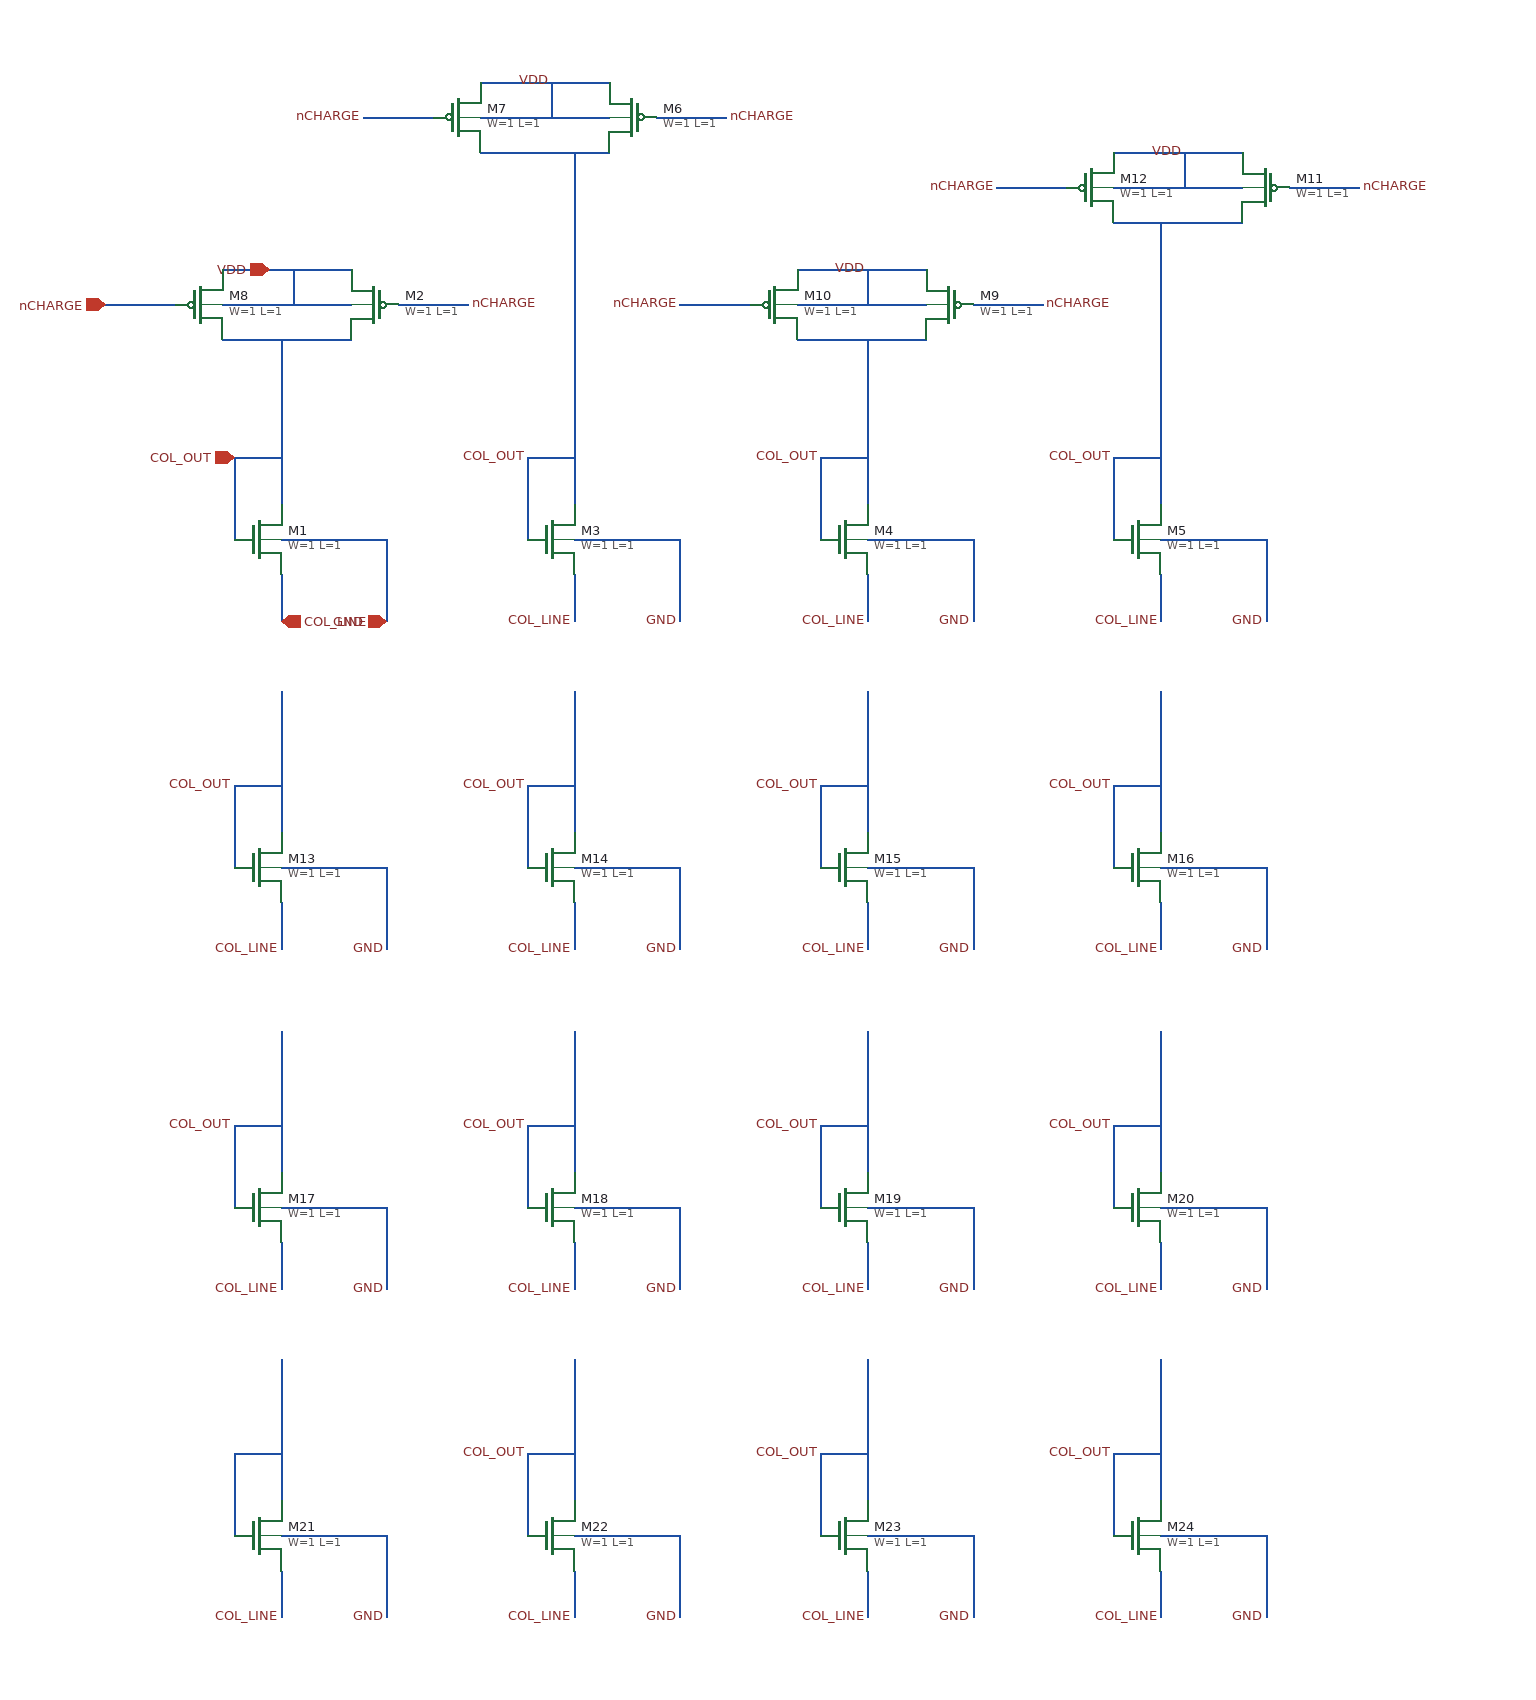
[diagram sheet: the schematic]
v {xschem version=3.4.8RC file_version=1.3}
G {}
K {}
V {}
S {}
F {}
E {}
P 4 1 -120 -60 {}
N 0 -80 0 40 {lab=COL_OUT}
N -40 0 -40 70 {lab=COL_OUT}
N -40 0 0 0 {lab=COL_OUT}
N 0 100 0 140 {lab=COL_LINE}
N 0 70 90 70 {lab=GND}
N 90 70 90 140 {lab=GND}
N 250 -80 250 40 {lab=COL_OUT}
N 210 0 210 70 {lab=COL_OUT}
N 210 0 250 0 {lab=COL_OUT}
N 250 100 250 140 {lab=COL_LINE}
N 250 70 340 70 {lab=GND}
N 340 70 340 140 {lab=GND}
N 500 -80 500 40 {lab=COL_OUT}
N 460 0 460 70 {lab=COL_OUT}
N 460 0 500 0 {lab=COL_OUT}
N 500 100 500 140 {lab=COL_LINE}
N 500 70 590 70 {lab=GND}
N 590 70 590 140 {lab=GND}
N 750 -80 750 40 {lab=COL_OUT}
N 710 0 710 70 {lab=COL_OUT}
N 710 0 750 0 {lab=COL_OUT}
N 750 100 750 140 {lab=COL_LINE}
N 750 70 840 70 {lab=GND}
N 840 70 840 140 {lab=GND}
N 320 -290 380 -290 {lab=nCHARGE}
N 70 -290 130 -290 {lab=nCHARGE}
N 170 -260 280 -260 {lab=COL_OUT}
N 250 -260 250 -80 {lab=COL_OUT}
N 170 -290 280 -290 {lab=VDD}
N 170 -320 280 -320 {lab=VDD}
N 230 -320 230 -290 {lab=VDD}
N 100 -130 160 -130 {lab=nCHARGE}
N -150 -130 -90 -130 {lab=nCHARGE}
N -50 -130 60 -130 {lab=VDD}
N -50 -160 60 -160 {lab=VDD}
N 10 -160 10 -130 {lab=VDD}
N -50 -100 60 -100 {lab=COL_OUT}
N 0 -100 0 -80 {lab=COL_OUT}
N 590 -130 650 -130 {lab=nCHARGE}
N 340 -130 400 -130 {lab=nCHARGE}
N 440 -130 550 -130 {lab=VDD}
N 440 -160 550 -160 {lab=VDD}
N 500 -160 500 -130 {lab=VDD}
N 440 -100 550 -100 {lab=COL_OUT}
N 500 -100 500 -80 {lab=COL_OUT}
N 860 -230 920 -230 {lab=nCHARGE}
N 610 -230 670 -230 {lab=nCHARGE}
N 710 -230 820 -230 {lab=VDD}
N 710 -260 820 -260 {lab=VDD}
N 770 -260 770 -230 {lab=VDD}
N 750 -200 750 -80 {lab=COL_OUT}
N 710 -200 820 -200 {lab=COL_OUT}
N 0 200 0 320 {lab=COL_OUT}
N -40 280 -40 350 {lab=COL_OUT}
N -40 280 0 280 {lab=COL_OUT}
N 0 380 0 420 {lab=#net1}
N 0 350 90 350 {lab=#net2}
N 90 350 90 420 {lab=#net2}
N 250 200 250 320 {lab=COL_OUT}
N 210 280 210 350 {lab=COL_OUT}
N 210 280 250 280 {lab=COL_OUT}
N 250 380 250 420 {lab=COL_LINE}
N 250 350 340 350 {lab=GND}
N 340 350 340 420 {lab=GND}
N 500 200 500 320 {lab=COL_OUT}
N 460 280 460 350 {lab=COL_OUT}
N 460 280 500 280 {lab=COL_OUT}
N 500 380 500 420 {lab=COL_LINE}
N 500 350 590 350 {lab=GND}
N 590 350 590 420 {lab=GND}
N 750 200 750 320 {lab=COL_OUT}
N 710 280 710 350 {lab=COL_OUT}
N 710 280 750 280 {lab=COL_OUT}
N 750 380 750 420 {lab=COL_LINE}
N 750 350 840 350 {lab=GND}
N 840 350 840 420 {lab=GND}
N 0 490 0 610 {lab=COL_OUT}
N -40 570 -40 640 {lab=COL_OUT}
N -40 570 0 570 {lab=COL_OUT}
N 0 670 0 710 {lab=#net3}
N 0 640 90 640 {lab=#net4}
N 90 640 90 710 {lab=#net4}
N 250 490 250 610 {lab=COL_OUT}
N 210 570 210 640 {lab=COL_OUT}
N 210 570 250 570 {lab=COL_OUT}
N 250 670 250 710 {lab=COL_LINE}
N 250 640 340 640 {lab=GND}
N 340 640 340 710 {lab=GND}
N 500 490 500 610 {lab=COL_OUT}
N 460 570 460 640 {lab=COL_OUT}
N 460 570 500 570 {lab=COL_OUT}
N 500 670 500 710 {lab=COL_LINE}
N 500 640 590 640 {lab=GND}
N 590 640 590 710 {lab=GND}
N 750 490 750 610 {lab=COL_OUT}
N 710 570 710 640 {lab=COL_OUT}
N 710 570 750 570 {lab=COL_OUT}
N 750 670 750 710 {lab=COL_LINE}
N 750 640 840 640 {lab=GND}
N 840 640 840 710 {lab=GND}
N 0 770 0 890 {lab=#net5}
N -40 850 -40 920 {lab=#net5}
N -40 850 0 850 {lab=#net5}
N 0 950 0 990 {lab=#net6}
N 0 920 90 920 {lab=#net7}
N 90 920 90 990 {lab=#net7}
N 250 770 250 890 {lab=COL_OUT}
N 210 850 210 920 {lab=COL_OUT}
N 210 850 250 850 {lab=COL_OUT}
N 250 950 250 990 {lab=COL_LINE}
N 250 920 340 920 {lab=GND}
N 340 920 340 990 {lab=GND}
N 500 770 500 890 {lab=COL_OUT}
N 460 850 460 920 {lab=COL_OUT}
N 460 850 500 850 {lab=COL_OUT}
N 500 950 500 990 {lab=COL_LINE}
N 500 920 590 920 {lab=GND}
N 590 920 590 990 {lab=GND}
N 750 770 750 890 {lab=COL_OUT}
N 710 850 710 920 {lab=COL_OUT}
N 710 850 750 850 {lab=COL_OUT}
N 750 950 750 990 {lab=COL_LINE}
N 750 920 840 920 {lab=GND}
N 840 920 840 990 {lab=GND}
C {sky130_fd_pr/nfet_01v8.sym} -20 70 0 0 {name=M1
W=1
L=1
nf=1 
mult=1
ad="expr('int((@nf + 1)/2) * @W / @nf * 0.29')"
pd="expr('2*int((@nf + 1)/2) * (@W / @nf + 0.29)')"
as="expr('int((@nf + 2)/2) * @W / @nf * 0.29')"
ps="expr('2*int((@nf + 2)/2) * (@W / @nf + 0.29)')"
nrd="expr('0.29 / @W ')" nrs="expr('0.29 / @W ')"
sa=0 sb=0 sd=0
model=nfet_01v8
spiceprefix=X
}
C {ipin.sym} -150 -130 0 0 {name=p1 lab=nCHARGE}
C {opin.sym} -40 0 0 1 {name=p2 lab=COL_OUT}
C {iopin.sym} -10 -160 3 0 {name=p3 lab=VDD}
C {iopin.sym} 90 140 0 0 {name=p5 lab=GND}
C {iopin.sym} 0 140 0 1 {name=p6 lab=COL_LINE}
C {sky130_fd_pr/nfet_01v8.sym} 230 70 0 0 {name=M3
W=1
L=1
nf=1 
mult=1
ad="expr('int((@nf + 1)/2) * @W / @nf * 0.29')"
pd="expr('2*int((@nf + 1)/2) * (@W / @nf + 0.29)')"
as="expr('int((@nf + 2)/2) * @W / @nf * 0.29')"
ps="expr('2*int((@nf + 2)/2) * (@W / @nf + 0.29)')"
nrd="expr('0.29 / @W ')" nrs="expr('0.29 / @W ')"
sa=0 sb=0 sd=0
model=nfet_01v8
spiceprefix=X
}
C {sky130_fd_pr/nfet_01v8.sym} 480 70 0 0 {name=M4
W=1
L=1
nf=1 
mult=1
ad="expr('int((@nf + 1)/2) * @W / @nf * 0.29')"
pd="expr('2*int((@nf + 1)/2) * (@W / @nf + 0.29)')"
as="expr('int((@nf + 2)/2) * @W / @nf * 0.29')"
ps="expr('2*int((@nf + 2)/2) * (@W / @nf + 0.29)')"
nrd="expr('0.29 / @W ')" nrs="expr('0.29 / @W ')"
sa=0 sb=0 sd=0
model=nfet_01v8
spiceprefix=X
}
C {sky130_fd_pr/nfet_01v8.sym} 730 70 0 0 {name=M5
W=1
L=1
nf=1 
mult=1
ad="expr('int((@nf + 1)/2) * @W / @nf * 0.29')"
pd="expr('2*int((@nf + 1)/2) * (@W / @nf + 0.29)')"
as="expr('int((@nf + 2)/2) * @W / @nf * 0.29')"
ps="expr('2*int((@nf + 2)/2) * (@W / @nf + 0.29)')"
nrd="expr('0.29 / @W ')" nrs="expr('0.29 / @W ')"
sa=0 sb=0 sd=0
model=nfet_01v8
spiceprefix=X
}
C {lab_wire.sym} 210 0 0 0 {name=p7 sig_type=std_logic lab=COL_OUT}
C {lab_wire.sym} 250 140 0 0 {name=p10 sig_type=std_logic lab=COL_LINE
}
C {lab_wire.sym} 340 140 0 0 {name=p8 sig_type=std_logic lab=GND
}
C {lab_wire.sym} 460 0 0 0 {name=p9 sig_type=std_logic lab=COL_OUT}
C {lab_wire.sym} 500 140 0 0 {name=p11 sig_type=std_logic lab=COL_LINE
}
C {lab_wire.sym} 590 140 0 0 {name=p12 sig_type=std_logic lab=GND
}
C {lab_wire.sym} 710 0 0 0 {name=p13 sig_type=std_logic lab=COL_OUT}
C {lab_wire.sym} 750 140 0 0 {name=p14 sig_type=std_logic lab=COL_LINE
}
C {lab_wire.sym} 840 140 0 0 {name=p15 sig_type=std_logic lab=GND
}
C {sky130_fd_pr/pfet_01v8.sym} 300 -290 0 1 {name=M6
W=1
L=1
nf=1
mult=1
ad="expr('int((@nf + 1)/2) * @W / @nf * 0.29')"
pd="expr('2*int((@nf + 1)/2) * (@W / @nf + 0.29)')"
as="expr('int((@nf + 2)/2) * @W / @nf * 0.29')"
ps="expr('2*int((@nf + 2)/2) * (@W / @nf + 0.29)')"
nrd="expr('0.29 / @W ')" nrs="expr('0.29 / @W ')"
sa=0 sb=0 sd=0
model=pfet_01v8
spiceprefix=X
}
C {sky130_fd_pr/pfet_01v8.sym} 150 -290 0 0 {name=M7
W=1
L=1
nf=1
mult=1
ad="expr('int((@nf + 1)/2) * @W / @nf * 0.29')"
pd="expr('2*int((@nf + 1)/2) * (@W / @nf + 0.29)')"
as="expr('int((@nf + 2)/2) * @W / @nf * 0.29')"
ps="expr('2*int((@nf + 2)/2) * (@W / @nf + 0.29)')"
nrd="expr('0.29 / @W ')" nrs="expr('0.29 / @W ')"
sa=0 sb=0 sd=0
model=pfet_01v8
spiceprefix=X
}
C {lab_wire.sym} 200 -320 0 1 {name=p16 sig_type=std_logic lab=VDD}
C {lab_wire.sym} 70 -290 0 0 {name=p18 sig_type=std_logic lab=nCHARGE}
C {lab_wire.sym} 380 -290 0 1 {name=p19 sig_type=std_logic lab=nCHARGE}
C {sky130_fd_pr/pfet_01v8.sym} 80 -130 0 1 {name=M2
W=1
L=1
nf=1
mult=1
ad="expr('int((@nf + 1)/2) * @W / @nf * 0.29')"
pd="expr('2*int((@nf + 1)/2) * (@W / @nf + 0.29)')"
as="expr('int((@nf + 2)/2) * @W / @nf * 0.29')"
ps="expr('2*int((@nf + 2)/2) * (@W / @nf + 0.29)')"
nrd="expr('0.29 / @W ')" nrs="expr('0.29 / @W ')"
sa=0 sb=0 sd=0
model=pfet_01v8
spiceprefix=X
}
C {sky130_fd_pr/pfet_01v8.sym} -70 -130 0 0 {name=M8
W=1
L=1
nf=1
mult=1
ad="expr('int((@nf + 1)/2) * @W / @nf * 0.29')"
pd="expr('2*int((@nf + 1)/2) * (@W / @nf + 0.29)')"
as="expr('int((@nf + 2)/2) * @W / @nf * 0.29')"
ps="expr('2*int((@nf + 2)/2) * (@W / @nf + 0.29)')"
nrd="expr('0.29 / @W ')" nrs="expr('0.29 / @W ')"
sa=0 sb=0 sd=0
model=pfet_01v8
spiceprefix=X
}
C {lab_wire.sym} 160 -130 0 1 {name=p20 sig_type=std_logic lab=nCHARGE}
C {sky130_fd_pr/pfet_01v8.sym} 570 -130 0 1 {name=M9
W=1
L=1
nf=1
mult=1
ad="expr('int((@nf + 1)/2) * @W / @nf * 0.29')"
pd="expr('2*int((@nf + 1)/2) * (@W / @nf + 0.29)')"
as="expr('int((@nf + 2)/2) * @W / @nf * 0.29')"
ps="expr('2*int((@nf + 2)/2) * (@W / @nf + 0.29)')"
nrd="expr('0.29 / @W ')" nrs="expr('0.29 / @W ')"
sa=0 sb=0 sd=0
model=pfet_01v8
spiceprefix=X
}
C {sky130_fd_pr/pfet_01v8.sym} 420 -130 0 0 {name=M10
W=1
L=1
nf=1
mult=1
ad="expr('int((@nf + 1)/2) * @W / @nf * 0.29')"
pd="expr('2*int((@nf + 1)/2) * (@W / @nf + 0.29)')"
as="expr('int((@nf + 2)/2) * @W / @nf * 0.29')"
ps="expr('2*int((@nf + 2)/2) * (@W / @nf + 0.29)')"
nrd="expr('0.29 / @W ')" nrs="expr('0.29 / @W ')"
sa=0 sb=0 sd=0
model=pfet_01v8
spiceprefix=X
}
C {lab_wire.sym} 470 -160 0 1 {name=p4 sig_type=std_logic lab=VDD}
C {lab_wire.sym} 340 -130 0 0 {name=p17 sig_type=std_logic lab=nCHARGE}
C {lab_wire.sym} 650 -130 0 1 {name=p21 sig_type=std_logic lab=nCHARGE}
C {sky130_fd_pr/pfet_01v8.sym} 840 -230 0 1 {name=M11
W=1
L=1
nf=1
mult=1
ad="expr('int((@nf + 1)/2) * @W / @nf * 0.29')"
pd="expr('2*int((@nf + 1)/2) * (@W / @nf + 0.29)')"
as="expr('int((@nf + 2)/2) * @W / @nf * 0.29')"
ps="expr('2*int((@nf + 2)/2) * (@W / @nf + 0.29)')"
nrd="expr('0.29 / @W ')" nrs="expr('0.29 / @W ')"
sa=0 sb=0 sd=0
model=pfet_01v8
spiceprefix=X
}
C {sky130_fd_pr/pfet_01v8.sym} 690 -230 0 0 {name=M12
W=1
L=1
nf=1
mult=1
ad="expr('int((@nf + 1)/2) * @W / @nf * 0.29')"
pd="expr('2*int((@nf + 1)/2) * (@W / @nf + 0.29)')"
as="expr('int((@nf + 2)/2) * @W / @nf * 0.29')"
ps="expr('2*int((@nf + 2)/2) * (@W / @nf + 0.29)')"
nrd="expr('0.29 / @W ')" nrs="expr('0.29 / @W ')"
sa=0 sb=0 sd=0
model=pfet_01v8
spiceprefix=X
}
C {lab_wire.sym} 740 -260 0 1 {name=p22 sig_type=std_logic lab=VDD}
C {lab_wire.sym} 610 -230 0 0 {name=p23 sig_type=std_logic lab=nCHARGE}
C {lab_wire.sym} 920 -230 0 1 {name=p24 sig_type=std_logic lab=nCHARGE}
C {sky130_fd_pr/nfet_01v8.sym} -20 350 0 0 {name=M13
W=1
L=1
nf=1 
mult=1
ad="expr('int((@nf + 1)/2) * @W / @nf * 0.29')"
pd="expr('2*int((@nf + 1)/2) * (@W / @nf + 0.29)')"
as="expr('int((@nf + 2)/2) * @W / @nf * 0.29')"
ps="expr('2*int((@nf + 2)/2) * (@W / @nf + 0.29)')"
nrd="expr('0.29 / @W ')" nrs="expr('0.29 / @W ')"
sa=0 sb=0 sd=0
model=nfet_01v8
spiceprefix=X
}
C {sky130_fd_pr/nfet_01v8.sym} 230 350 0 0 {name=M14
W=1
L=1
nf=1 
mult=1
ad="expr('int((@nf + 1)/2) * @W / @nf * 0.29')"
pd="expr('2*int((@nf + 1)/2) * (@W / @nf + 0.29)')"
as="expr('int((@nf + 2)/2) * @W / @nf * 0.29')"
ps="expr('2*int((@nf + 2)/2) * (@W / @nf + 0.29)')"
nrd="expr('0.29 / @W ')" nrs="expr('0.29 / @W ')"
sa=0 sb=0 sd=0
model=nfet_01v8
spiceprefix=X
}
C {sky130_fd_pr/nfet_01v8.sym} 480 350 0 0 {name=M15
W=1
L=1
nf=1 
mult=1
ad="expr('int((@nf + 1)/2) * @W / @nf * 0.29')"
pd="expr('2*int((@nf + 1)/2) * (@W / @nf + 0.29)')"
as="expr('int((@nf + 2)/2) * @W / @nf * 0.29')"
ps="expr('2*int((@nf + 2)/2) * (@W / @nf + 0.29)')"
nrd="expr('0.29 / @W ')" nrs="expr('0.29 / @W ')"
sa=0 sb=0 sd=0
model=nfet_01v8
spiceprefix=X
}
C {sky130_fd_pr/nfet_01v8.sym} 730 350 0 0 {name=M16
W=1
L=1
nf=1 
mult=1
ad="expr('int((@nf + 1)/2) * @W / @nf * 0.29')"
pd="expr('2*int((@nf + 1)/2) * (@W / @nf + 0.29)')"
as="expr('int((@nf + 2)/2) * @W / @nf * 0.29')"
ps="expr('2*int((@nf + 2)/2) * (@W / @nf + 0.29)')"
nrd="expr('0.29 / @W ')" nrs="expr('0.29 / @W ')"
sa=0 sb=0 sd=0
model=nfet_01v8
spiceprefix=X
}
C {lab_wire.sym} 210 280 0 0 {name=p28 sig_type=std_logic lab=COL_OUT}
C {lab_wire.sym} 250 420 0 0 {name=p29 sig_type=std_logic lab=COL_LINE
}
C {lab_wire.sym} 340 420 0 0 {name=p30 sig_type=std_logic lab=GND
}
C {lab_wire.sym} 460 280 0 0 {name=p31 sig_type=std_logic lab=COL_OUT}
C {lab_wire.sym} 500 420 0 0 {name=p32 sig_type=std_logic lab=COL_LINE
}
C {lab_wire.sym} 590 420 0 0 {name=p33 sig_type=std_logic lab=GND
}
C {lab_wire.sym} 710 280 0 0 {name=p34 sig_type=std_logic lab=COL_OUT}
C {lab_wire.sym} 750 420 0 0 {name=p35 sig_type=std_logic lab=COL_LINE
}
C {lab_wire.sym} 840 420 0 0 {name=p36 sig_type=std_logic lab=GND
}
C {sky130_fd_pr/nfet_01v8.sym} -20 640 0 0 {name=M17
W=1
L=1
nf=1 
mult=1
ad="expr('int((@nf + 1)/2) * @W / @nf * 0.29')"
pd="expr('2*int((@nf + 1)/2) * (@W / @nf + 0.29)')"
as="expr('int((@nf + 2)/2) * @W / @nf * 0.29')"
ps="expr('2*int((@nf + 2)/2) * (@W / @nf + 0.29)')"
nrd="expr('0.29 / @W ')" nrs="expr('0.29 / @W ')"
sa=0 sb=0 sd=0
model=nfet_01v8
spiceprefix=X
}
C {sky130_fd_pr/nfet_01v8.sym} 230 640 0 0 {name=M18
W=1
L=1
nf=1 
mult=1
ad="expr('int((@nf + 1)/2) * @W / @nf * 0.29')"
pd="expr('2*int((@nf + 1)/2) * (@W / @nf + 0.29)')"
as="expr('int((@nf + 2)/2) * @W / @nf * 0.29')"
ps="expr('2*int((@nf + 2)/2) * (@W / @nf + 0.29)')"
nrd="expr('0.29 / @W ')" nrs="expr('0.29 / @W ')"
sa=0 sb=0 sd=0
model=nfet_01v8
spiceprefix=X
}
C {sky130_fd_pr/nfet_01v8.sym} 480 640 0 0 {name=M19
W=1
L=1
nf=1 
mult=1
ad="expr('int((@nf + 1)/2) * @W / @nf * 0.29')"
pd="expr('2*int((@nf + 1)/2) * (@W / @nf + 0.29)')"
as="expr('int((@nf + 2)/2) * @W / @nf * 0.29')"
ps="expr('2*int((@nf + 2)/2) * (@W / @nf + 0.29)')"
nrd="expr('0.29 / @W ')" nrs="expr('0.29 / @W ')"
sa=0 sb=0 sd=0
model=nfet_01v8
spiceprefix=X
}
C {sky130_fd_pr/nfet_01v8.sym} 730 640 0 0 {name=M20
W=1
L=1
nf=1 
mult=1
ad="expr('int((@nf + 1)/2) * @W / @nf * 0.29')"
pd="expr('2*int((@nf + 1)/2) * (@W / @nf + 0.29)')"
as="expr('int((@nf + 2)/2) * @W / @nf * 0.29')"
ps="expr('2*int((@nf + 2)/2) * (@W / @nf + 0.29)')"
nrd="expr('0.29 / @W ')" nrs="expr('0.29 / @W ')"
sa=0 sb=0 sd=0
model=nfet_01v8
spiceprefix=X
}
C {lab_wire.sym} 210 570 0 0 {name=p40 sig_type=std_logic lab=COL_OUT}
C {lab_wire.sym} 250 710 0 0 {name=p41 sig_type=std_logic lab=COL_LINE
}
C {lab_wire.sym} 340 710 0 0 {name=p42 sig_type=std_logic lab=GND
}
C {lab_wire.sym} 460 570 0 0 {name=p43 sig_type=std_logic lab=COL_OUT}
C {lab_wire.sym} 500 710 0 0 {name=p44 sig_type=std_logic lab=COL_LINE
}
C {lab_wire.sym} 590 710 0 0 {name=p45 sig_type=std_logic lab=GND
}
C {lab_wire.sym} 710 570 0 0 {name=p46 sig_type=std_logic lab=COL_OUT}
C {lab_wire.sym} 750 710 0 0 {name=p47 sig_type=std_logic lab=COL_LINE
}
C {lab_wire.sym} 840 710 0 0 {name=p48 sig_type=std_logic lab=GND
}
C {sky130_fd_pr/nfet_01v8.sym} -20 920 0 0 {name=M21
W=1
L=1
nf=1 
mult=1
ad="expr('int((@nf + 1)/2) * @W / @nf * 0.29')"
pd="expr('2*int((@nf + 1)/2) * (@W / @nf + 0.29)')"
as="expr('int((@nf + 2)/2) * @W / @nf * 0.29')"
ps="expr('2*int((@nf + 2)/2) * (@W / @nf + 0.29)')"
nrd="expr('0.29 / @W ')" nrs="expr('0.29 / @W ')"
sa=0 sb=0 sd=0
model=nfet_01v8
spiceprefix=X
}
C {sky130_fd_pr/nfet_01v8.sym} 230 920 0 0 {name=M22
W=1
L=1
nf=1 
mult=1
ad="expr('int((@nf + 1)/2) * @W / @nf * 0.29')"
pd="expr('2*int((@nf + 1)/2) * (@W / @nf + 0.29)')"
as="expr('int((@nf + 2)/2) * @W / @nf * 0.29')"
ps="expr('2*int((@nf + 2)/2) * (@W / @nf + 0.29)')"
nrd="expr('0.29 / @W ')" nrs="expr('0.29 / @W ')"
sa=0 sb=0 sd=0
model=nfet_01v8
spiceprefix=X
}
C {sky130_fd_pr/nfet_01v8.sym} 480 920 0 0 {name=M23
W=1
L=1
nf=1 
mult=1
ad="expr('int((@nf + 1)/2) * @W / @nf * 0.29')"
pd="expr('2*int((@nf + 1)/2) * (@W / @nf + 0.29)')"
as="expr('int((@nf + 2)/2) * @W / @nf * 0.29')"
ps="expr('2*int((@nf + 2)/2) * (@W / @nf + 0.29)')"
nrd="expr('0.29 / @W ')" nrs="expr('0.29 / @W ')"
sa=0 sb=0 sd=0
model=nfet_01v8
spiceprefix=X
}
C {sky130_fd_pr/nfet_01v8.sym} 730 920 0 0 {name=M24
W=1
L=1
nf=1 
mult=1
ad="expr('int((@nf + 1)/2) * @W / @nf * 0.29')"
pd="expr('2*int((@nf + 1)/2) * (@W / @nf + 0.29)')"
as="expr('int((@nf + 2)/2) * @W / @nf * 0.29')"
ps="expr('2*int((@nf + 2)/2) * (@W / @nf + 0.29)')"
nrd="expr('0.29 / @W ')" nrs="expr('0.29 / @W ')"
sa=0 sb=0 sd=0
model=nfet_01v8
spiceprefix=X
}
C {lab_wire.sym} 210 850 0 0 {name=p52 sig_type=std_logic lab=COL_OUT}
C {lab_wire.sym} 250 990 0 0 {name=p53 sig_type=std_logic lab=COL_LINE
}
C {lab_wire.sym} 340 990 0 0 {name=p54 sig_type=std_logic lab=GND
}
C {lab_wire.sym} 460 850 0 0 {name=p55 sig_type=std_logic lab=COL_OUT}
C {lab_wire.sym} 500 990 0 0 {name=p56 sig_type=std_logic lab=COL_LINE
}
C {lab_wire.sym} 590 990 0 0 {name=p57 sig_type=std_logic lab=GND
}
C {lab_wire.sym} 710 850 0 0 {name=p58 sig_type=std_logic lab=COL_OUT}
C {lab_wire.sym} 750 990 0 0 {name=p59 sig_type=std_logic lab=COL_LINE
}
C {lab_wire.sym} 840 990 0 0 {name=p60 sig_type=std_logic lab=GND
}
C {lab_wire.sym} -40 570 0 0 {name=p37 sig_type=std_logic lab=COL_OUT}
C {lab_wire.sym} -40 280 0 0 {name=p25 sig_type=std_logic lab=COL_OUT}
C {lab_wire.sym} 0 990 0 0 {name=p26 sig_type=std_logic lab=COL_LINE
}
C {lab_wire.sym} 90 990 0 0 {name=p27 sig_type=std_logic lab=GND
}
C {lab_wire.sym} 0 710 0 0 {name=p38 sig_type=std_logic lab=COL_LINE
}
C {lab_wire.sym} 90 710 0 0 {name=p39 sig_type=std_logic lab=GND
}
C {lab_wire.sym} 0 420 0 0 {name=p49 sig_type=std_logic lab=COL_LINE
}
C {lab_wire.sym} 90 420 0 0 {name=p50 sig_type=std_logic lab=GND
}
